VERSION 5.7 ;
  NOWIREEXTENSIONATPIN ON ;
  DIVIDERCHAR "/" ;
  BUSBITCHARS "[]" ;
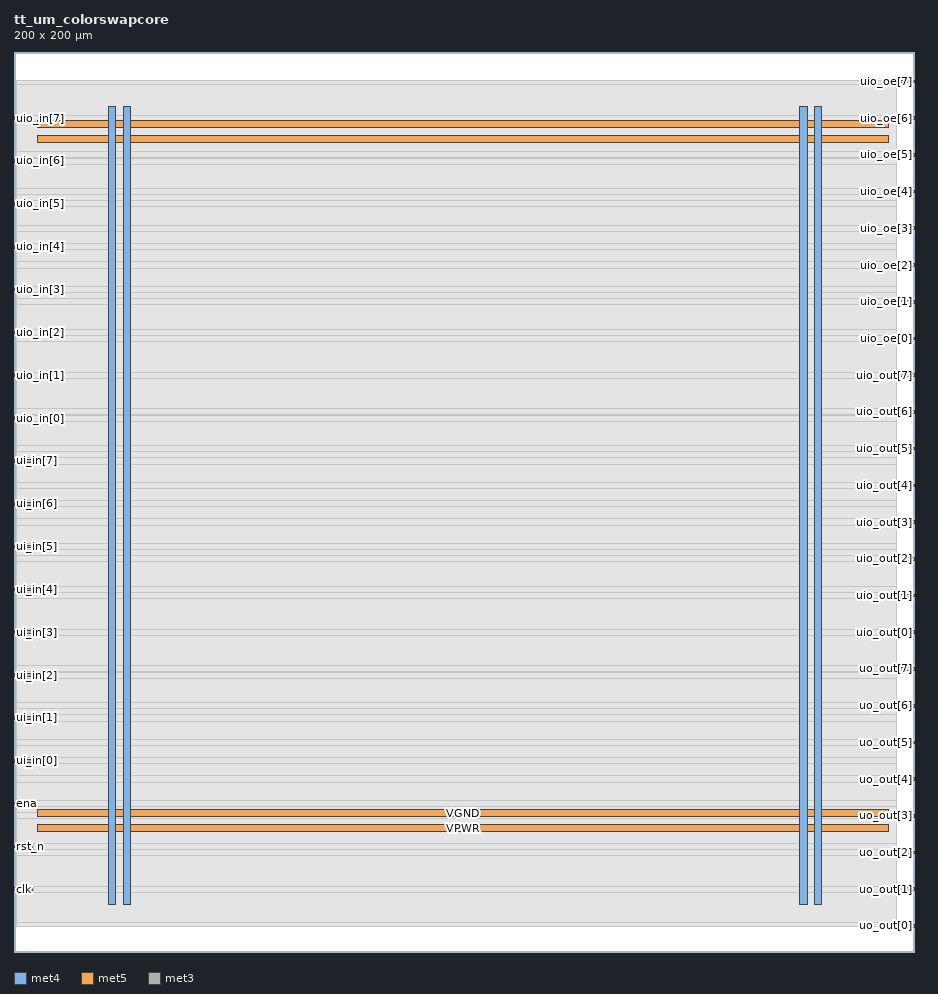
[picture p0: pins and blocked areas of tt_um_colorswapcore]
MACRO tt_um_colorswapcore
  CLASS BLOCK ;
  FOREIGN tt_um_colorswapcore ;
  ORIGIN 0.000 0.000 ;
  SIZE 200.000 BY 200.000 ;
  PIN VGND
    DIRECTION INOUT ;
    USE GROUND ;
    PORT
      LAYER met4 ;
        RECT 24.340 10.640 25.940 187.920 ;
    END
    PORT
      LAYER met4 ;
        RECT 177.940 10.640 179.540 187.920 ;
    END
    PORT
      LAYER met5 ;
        RECT 5.280 30.030 194.360 31.630 ;
    END
    PORT
      LAYER met5 ;
        RECT 5.280 183.210 194.360 184.810 ;
    END
  END VGND
  PIN VPWR
    DIRECTION INOUT ;
    USE POWER ;
    PORT
      LAYER met4 ;
        RECT 21.040 10.640 22.640 187.920 ;
    END
    PORT
      LAYER met4 ;
        RECT 174.640 10.640 176.240 187.920 ;
    END
    PORT
      LAYER met5 ;
        RECT 5.280 26.730 194.360 28.330 ;
    END
    PORT
      LAYER met5 ;
        RECT 5.280 179.910 194.360 181.510 ;
    END
  END VPWR
  PIN clk
    DIRECTION INPUT ;
    USE SIGNAL ;
    ANTENNAGATEAREA 0.852000 ;
    PORT
      LAYER met3 ;
        RECT 0.000 13.640 4.000 14.240 ;
    END
  END clk
  PIN ena
    DIRECTION INPUT ;
    USE SIGNAL ;
    PORT
      LAYER met3 ;
        RECT 0.000 32.680 4.000 33.280 ;
    END
  END ena
  PIN rst_n
    DIRECTION INPUT ;
    USE SIGNAL ;
    ANTENNAGATEAREA 0.196500 ;
    PORT
      LAYER met3 ;
        RECT 0.000 23.160 4.000 23.760 ;
    END
  END rst_n
  PIN ui_in[0]
    DIRECTION INPUT ;
    USE SIGNAL ;
    ANTENNAGATEAREA 0.196500 ;
    PORT
      LAYER met3 ;
        RECT 0.000 42.200 4.000 42.800 ;
    END
  END ui_in[0]
  PIN ui_in[1]
    DIRECTION INPUT ;
    USE SIGNAL ;
    ANTENNAGATEAREA 0.196500 ;
    PORT
      LAYER met3 ;
        RECT 0.000 51.720 4.000 52.320 ;
    END
  END ui_in[1]
  PIN ui_in[2]
    DIRECTION INPUT ;
    USE SIGNAL ;
    ANTENNAGATEAREA 0.196500 ;
    PORT
      LAYER met3 ;
        RECT 0.000 61.240 4.000 61.840 ;
    END
  END ui_in[2]
  PIN ui_in[3]
    DIRECTION INPUT ;
    USE SIGNAL ;
    PORT
      LAYER met3 ;
        RECT 0.000 70.760 4.000 71.360 ;
    END
  END ui_in[3]
  PIN ui_in[4]
    DIRECTION INPUT ;
    USE SIGNAL ;
    PORT
      LAYER met3 ;
        RECT 0.000 80.280 4.000 80.880 ;
    END
  END ui_in[4]
  PIN ui_in[5]
    DIRECTION INPUT ;
    USE SIGNAL ;
    PORT
      LAYER met3 ;
        RECT 0.000 89.800 4.000 90.400 ;
    END
  END ui_in[5]
  PIN ui_in[6]
    DIRECTION INPUT ;
    USE SIGNAL ;
    PORT
      LAYER met3 ;
        RECT 0.000 99.320 4.000 99.920 ;
    END
  END ui_in[6]
  PIN ui_in[7]
    DIRECTION INPUT ;
    USE SIGNAL ;
    PORT
      LAYER met3 ;
        RECT 0.000 108.840 4.000 109.440 ;
    END
  END ui_in[7]
  PIN uio_in[0]
    DIRECTION INPUT ;
    USE SIGNAL ;
    ANTENNAGATEAREA 0.196500 ;
    PORT
      LAYER met3 ;
        RECT 0.000 118.360 4.000 118.960 ;
    END
  END uio_in[0]
  PIN uio_in[1]
    DIRECTION INPUT ;
    USE SIGNAL ;
    ANTENNAGATEAREA 0.196500 ;
    PORT
      LAYER met3 ;
        RECT 0.000 127.880 4.000 128.480 ;
    END
  END uio_in[1]
  PIN uio_in[2]
    DIRECTION INPUT ;
    USE SIGNAL ;
    ANTENNAGATEAREA 0.196500 ;
    PORT
      LAYER met3 ;
        RECT 0.000 137.400 4.000 138.000 ;
    END
  END uio_in[2]
  PIN uio_in[3]
    DIRECTION INPUT ;
    USE SIGNAL ;
    PORT
      LAYER met3 ;
        RECT 0.000 146.920 4.000 147.520 ;
    END
  END uio_in[3]
  PIN uio_in[4]
    DIRECTION INPUT ;
    USE SIGNAL ;
    PORT
      LAYER met3 ;
        RECT 0.000 156.440 4.000 157.040 ;
    END
  END uio_in[4]
  PIN uio_in[5]
    DIRECTION INPUT ;
    USE SIGNAL ;
    PORT
      LAYER met3 ;
        RECT 0.000 165.960 4.000 166.560 ;
    END
  END uio_in[5]
  PIN uio_in[6]
    DIRECTION INPUT ;
    USE SIGNAL ;
    PORT
      LAYER met3 ;
        RECT 0.000 175.480 4.000 176.080 ;
    END
  END uio_in[6]
  PIN uio_in[7]
    DIRECTION INPUT ;
    USE SIGNAL ;
    PORT
      LAYER met3 ;
        RECT 0.000 185.000 4.000 185.600 ;
    END
  END uio_in[7]
  PIN uio_oe[0]
    DIRECTION OUTPUT ;
    USE SIGNAL ;
    PORT
      LAYER met3 ;
        RECT 196.000 136.040 200.000 136.640 ;
    END
  END uio_oe[0]
  PIN uio_oe[1]
    DIRECTION OUTPUT ;
    USE SIGNAL ;
    PORT
      LAYER met3 ;
        RECT 196.000 144.200 200.000 144.800 ;
    END
  END uio_oe[1]
  PIN uio_oe[2]
    DIRECTION OUTPUT ;
    USE SIGNAL ;
    PORT
      LAYER met3 ;
        RECT 196.000 152.360 200.000 152.960 ;
    END
  END uio_oe[2]
  PIN uio_oe[3]
    DIRECTION OUTPUT ;
    USE SIGNAL ;
    PORT
      LAYER met3 ;
        RECT 196.000 160.520 200.000 161.120 ;
    END
  END uio_oe[3]
  PIN uio_oe[4]
    DIRECTION OUTPUT ;
    USE SIGNAL ;
    PORT
      LAYER met3 ;
        RECT 196.000 168.680 200.000 169.280 ;
    END
  END uio_oe[4]
  PIN uio_oe[5]
    DIRECTION OUTPUT ;
    USE SIGNAL ;
    PORT
      LAYER met3 ;
        RECT 196.000 176.840 200.000 177.440 ;
    END
  END uio_oe[5]
  PIN uio_oe[6]
    DIRECTION OUTPUT ;
    USE SIGNAL ;
    PORT
      LAYER met3 ;
        RECT 196.000 185.000 200.000 185.600 ;
    END
  END uio_oe[6]
  PIN uio_oe[7]
    DIRECTION OUTPUT ;
    USE SIGNAL ;
    PORT
      LAYER met3 ;
        RECT 196.000 193.160 200.000 193.760 ;
    END
  END uio_oe[7]
  PIN uio_out[0]
    DIRECTION OUTPUT ;
    USE SIGNAL ;
    PORT
      LAYER met3 ;
        RECT 196.000 70.760 200.000 71.360 ;
    END
  END uio_out[0]
  PIN uio_out[1]
    DIRECTION OUTPUT ;
    USE SIGNAL ;
    PORT
      LAYER met3 ;
        RECT 196.000 78.920 200.000 79.520 ;
    END
  END uio_out[1]
  PIN uio_out[2]
    DIRECTION OUTPUT ;
    USE SIGNAL ;
    PORT
      LAYER met3 ;
        RECT 196.000 87.080 200.000 87.680 ;
    END
  END uio_out[2]
  PIN uio_out[3]
    DIRECTION OUTPUT ;
    USE SIGNAL ;
    PORT
      LAYER met3 ;
        RECT 196.000 95.240 200.000 95.840 ;
    END
  END uio_out[3]
  PIN uio_out[4]
    DIRECTION OUTPUT ;
    USE SIGNAL ;
    PORT
      LAYER met3 ;
        RECT 196.000 103.400 200.000 104.000 ;
    END
  END uio_out[4]
  PIN uio_out[5]
    DIRECTION OUTPUT ;
    USE SIGNAL ;
    PORT
      LAYER met3 ;
        RECT 196.000 111.560 200.000 112.160 ;
    END
  END uio_out[5]
  PIN uio_out[6]
    DIRECTION OUTPUT ;
    USE SIGNAL ;
    PORT
      LAYER met3 ;
        RECT 196.000 119.720 200.000 120.320 ;
    END
  END uio_out[6]
  PIN uio_out[7]
    DIRECTION OUTPUT ;
    USE SIGNAL ;
    PORT
      LAYER met3 ;
        RECT 196.000 127.880 200.000 128.480 ;
    END
  END uio_out[7]
  PIN uo_out[0]
    DIRECTION OUTPUT ;
    USE SIGNAL ;
    ANTENNADIFFAREA 0.340600 ;
    PORT
      LAYER met3 ;
        RECT 196.000 5.480 200.000 6.080 ;
    END
  END uo_out[0]
  PIN uo_out[1]
    DIRECTION OUTPUT ;
    USE SIGNAL ;
    ANTENNADIFFAREA 0.340600 ;
    PORT
      LAYER met3 ;
        RECT 196.000 13.640 200.000 14.240 ;
    END
  END uo_out[1]
  PIN uo_out[2]
    DIRECTION OUTPUT ;
    USE SIGNAL ;
    ANTENNADIFFAREA 0.340600 ;
    PORT
      LAYER met3 ;
        RECT 196.000 21.800 200.000 22.400 ;
    END
  END uo_out[2]
  PIN uo_out[3]
    DIRECTION OUTPUT ;
    USE SIGNAL ;
    ANTENNADIFFAREA 0.340600 ;
    PORT
      LAYER met3 ;
        RECT 196.000 29.960 200.000 30.560 ;
    END
  END uo_out[3]
  PIN uo_out[4]
    DIRECTION OUTPUT ;
    USE SIGNAL ;
    ANTENNADIFFAREA 0.340600 ;
    PORT
      LAYER met3 ;
        RECT 196.000 38.120 200.000 38.720 ;
    END
  END uo_out[4]
  PIN uo_out[5]
    DIRECTION OUTPUT ;
    USE SIGNAL ;
    PORT
      LAYER met3 ;
        RECT 196.000 46.280 200.000 46.880 ;
    END
  END uo_out[5]
  PIN uo_out[6]
    DIRECTION OUTPUT ;
    USE SIGNAL ;
    PORT
      LAYER met3 ;
        RECT 196.000 54.440 200.000 55.040 ;
    END
  END uo_out[6]
  PIN uo_out[7]
    DIRECTION OUTPUT ;
    USE SIGNAL ;
    PORT
      LAYER met3 ;
        RECT 196.000 62.600 200.000 63.200 ;
    END
  END uo_out[7]
  OBS
      LAYER nwell ;
        RECT 5.330 10.795 194.310 187.870 ;
      LAYER li1 ;
        RECT 5.520 10.795 194.120 187.765 ;
      LAYER met1 ;
        RECT 0.530 10.640 194.120 187.920 ;
      LAYER met2 ;
        RECT 0.550 5.595 192.650 193.645 ;
      LAYER met3 ;
        RECT 0.525 192.760 195.600 193.625 ;
        RECT 0.525 186.000 196.000 192.760 ;
        RECT 4.400 184.600 195.600 186.000 ;
        RECT 0.525 177.840 196.000 184.600 ;
        RECT 0.525 176.480 195.600 177.840 ;
        RECT 4.400 176.440 195.600 176.480 ;
        RECT 4.400 175.080 196.000 176.440 ;
        RECT 0.525 169.680 196.000 175.080 ;
        RECT 0.525 168.280 195.600 169.680 ;
        RECT 0.525 166.960 196.000 168.280 ;
        RECT 4.400 165.560 196.000 166.960 ;
        RECT 0.525 161.520 196.000 165.560 ;
        RECT 0.525 160.120 195.600 161.520 ;
        RECT 0.525 157.440 196.000 160.120 ;
        RECT 4.400 156.040 196.000 157.440 ;
        RECT 0.525 153.360 196.000 156.040 ;
        RECT 0.525 151.960 195.600 153.360 ;
        RECT 0.525 147.920 196.000 151.960 ;
        RECT 4.400 146.520 196.000 147.920 ;
        RECT 0.525 145.200 196.000 146.520 ;
        RECT 0.525 143.800 195.600 145.200 ;
        RECT 0.525 138.400 196.000 143.800 ;
        RECT 4.400 137.040 196.000 138.400 ;
        RECT 4.400 137.000 195.600 137.040 ;
        RECT 0.525 135.640 195.600 137.000 ;
        RECT 0.525 128.880 196.000 135.640 ;
        RECT 4.400 127.480 195.600 128.880 ;
        RECT 0.525 120.720 196.000 127.480 ;
        RECT 0.525 119.360 195.600 120.720 ;
        RECT 4.400 119.320 195.600 119.360 ;
        RECT 4.400 117.960 196.000 119.320 ;
        RECT 0.525 112.560 196.000 117.960 ;
        RECT 0.525 111.160 195.600 112.560 ;
        RECT 0.525 109.840 196.000 111.160 ;
        RECT 4.400 108.440 196.000 109.840 ;
        RECT 0.525 104.400 196.000 108.440 ;
        RECT 0.525 103.000 195.600 104.400 ;
        RECT 0.525 100.320 196.000 103.000 ;
        RECT 4.400 98.920 196.000 100.320 ;
        RECT 0.525 96.240 196.000 98.920 ;
        RECT 0.525 94.840 195.600 96.240 ;
        RECT 0.525 90.800 196.000 94.840 ;
        RECT 4.400 89.400 196.000 90.800 ;
        RECT 0.525 88.080 196.000 89.400 ;
        RECT 0.525 86.680 195.600 88.080 ;
        RECT 0.525 81.280 196.000 86.680 ;
        RECT 4.400 79.920 196.000 81.280 ;
        RECT 4.400 79.880 195.600 79.920 ;
        RECT 0.525 78.520 195.600 79.880 ;
        RECT 0.525 71.760 196.000 78.520 ;
        RECT 4.400 70.360 195.600 71.760 ;
        RECT 0.525 63.600 196.000 70.360 ;
        RECT 0.525 62.240 195.600 63.600 ;
        RECT 4.400 62.200 195.600 62.240 ;
        RECT 4.400 60.840 196.000 62.200 ;
        RECT 0.525 55.440 196.000 60.840 ;
        RECT 0.525 54.040 195.600 55.440 ;
        RECT 0.525 52.720 196.000 54.040 ;
        RECT 4.400 51.320 196.000 52.720 ;
        RECT 0.525 47.280 196.000 51.320 ;
        RECT 0.525 45.880 195.600 47.280 ;
        RECT 0.525 43.200 196.000 45.880 ;
        RECT 4.400 41.800 196.000 43.200 ;
        RECT 0.525 39.120 196.000 41.800 ;
        RECT 0.525 37.720 195.600 39.120 ;
        RECT 0.525 33.680 196.000 37.720 ;
        RECT 4.400 32.280 196.000 33.680 ;
        RECT 0.525 30.960 196.000 32.280 ;
        RECT 0.525 29.560 195.600 30.960 ;
        RECT 0.525 24.160 196.000 29.560 ;
        RECT 4.400 22.800 196.000 24.160 ;
        RECT 4.400 22.760 195.600 22.800 ;
        RECT 0.525 21.400 195.600 22.760 ;
        RECT 0.525 14.640 196.000 21.400 ;
        RECT 4.400 13.240 195.600 14.640 ;
        RECT 0.525 6.480 196.000 13.240 ;
        RECT 0.525 5.615 195.600 6.480 ;
  END
END tt_um_colorswapcore
END LIBRARY

